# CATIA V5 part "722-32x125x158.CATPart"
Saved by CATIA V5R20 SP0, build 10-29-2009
Part number: 722-32x125x158
Definition: NONE
Nomenclature: 722-32x125x158
Source: Unknown
Description: 722-32x125x158
Bounding box of the stored display mesh (mm): x -16 to 16, y -16 to 16, z -110 to 48
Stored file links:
  C:\Users\Utente\Desktop\IO LAVORO\3D X SITO CF\X SITO\722\722-32x125x158.CATPart

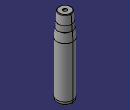
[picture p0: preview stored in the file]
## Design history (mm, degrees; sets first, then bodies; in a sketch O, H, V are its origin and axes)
Body1 "722-32x125x158" (main body)
  Solid1: solid without history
